VERSION 5.7 ;
  NOWIREEXTENSIONATPIN ON ;
  DIVIDERCHAR "/" ;
  BUSBITCHARS "[]" ;
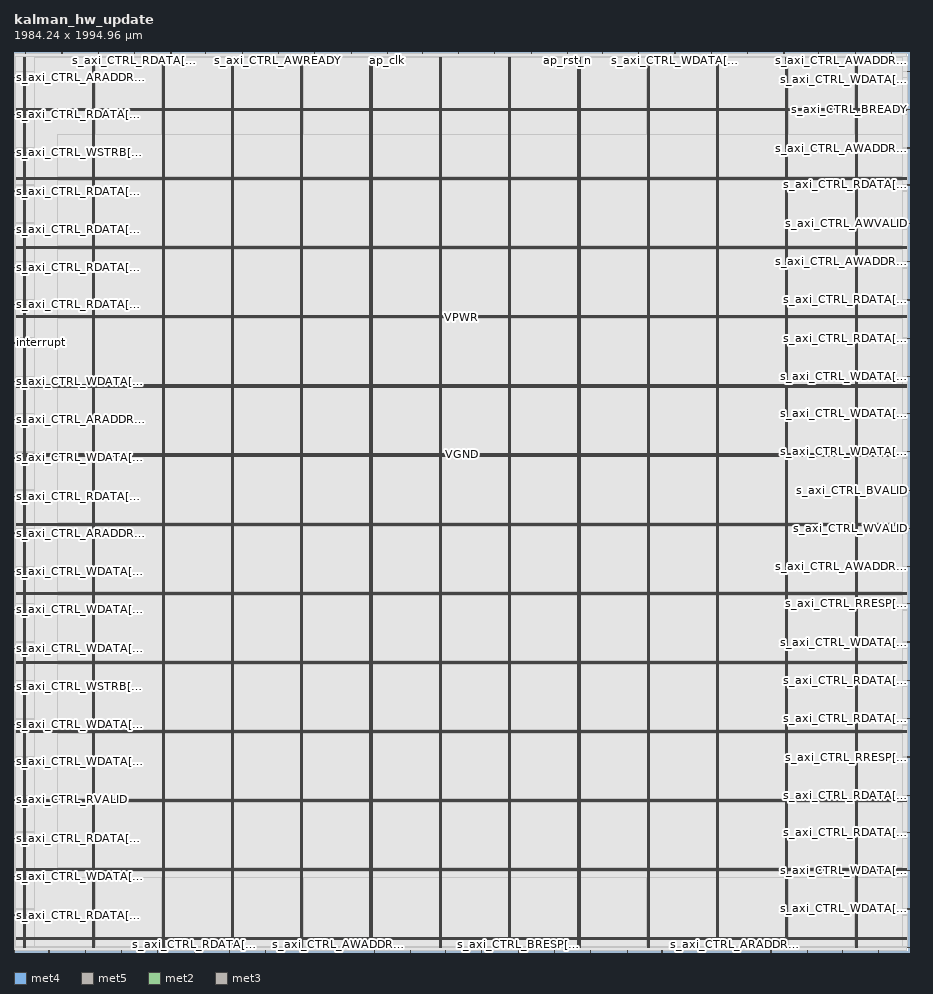
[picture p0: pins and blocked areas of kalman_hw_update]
MACRO kalman_hw_update
  CLASS BLOCK ;
  FOREIGN kalman_hw_update ;
  ORIGIN 0.000 0.000 ;
  SIZE 1984.245 BY 1994.965 ;
  PIN VGND
    DIRECTION INOUT ;
    USE GROUND ;
    PORT
      LAYER met4 ;
        RECT 24.340 10.640 25.940 1983.120 ;
    END
    PORT
      LAYER met4 ;
        RECT 177.940 10.640 179.540 1983.120 ;
    END
    PORT
      LAYER met4 ;
        RECT 331.540 10.640 333.140 1983.120 ;
    END
    PORT
      LAYER met4 ;
        RECT 485.140 10.640 486.740 1983.120 ;
    END
    PORT
      LAYER met4 ;
        RECT 638.740 10.640 640.340 1983.120 ;
    END
    PORT
      LAYER met4 ;
        RECT 792.340 10.640 793.940 1983.120 ;
    END
    PORT
      LAYER met4 ;
        RECT 945.940 10.640 947.540 1983.120 ;
    END
    PORT
      LAYER met4 ;
        RECT 1099.540 10.640 1101.140 1983.120 ;
    END
    PORT
      LAYER met4 ;
        RECT 1253.140 10.640 1254.740 1983.120 ;
    END
    PORT
      LAYER met4 ;
        RECT 1406.740 10.640 1408.340 1983.120 ;
    END
    PORT
      LAYER met4 ;
        RECT 1560.340 10.640 1561.940 1983.120 ;
    END
    PORT
      LAYER met4 ;
        RECT 1713.940 10.640 1715.540 1983.120 ;
    END
    PORT
      LAYER met4 ;
        RECT 1867.540 10.640 1869.140 1983.120 ;
    END
    PORT
      LAYER met5 ;
        RECT 5.280 30.030 1978.700 31.630 ;
    END
    PORT
      LAYER met5 ;
        RECT 5.280 183.210 1978.700 184.810 ;
    END
    PORT
      LAYER met5 ;
        RECT 5.280 336.390 1978.700 337.990 ;
    END
    PORT
      LAYER met5 ;
        RECT 5.280 489.570 1978.700 491.170 ;
    END
    PORT
      LAYER met5 ;
        RECT 5.280 642.750 1978.700 644.350 ;
    END
    PORT
      LAYER met5 ;
        RECT 5.280 795.930 1978.700 797.530 ;
    END
    PORT
      LAYER met5 ;
        RECT 5.280 949.110 1978.700 950.710 ;
    END
    PORT
      LAYER met5 ;
        RECT 5.280 1102.290 1978.700 1103.890 ;
    END
    PORT
      LAYER met5 ;
        RECT 5.280 1255.470 1978.700 1257.070 ;
    END
    PORT
      LAYER met5 ;
        RECT 5.280 1408.650 1978.700 1410.250 ;
    END
    PORT
      LAYER met5 ;
        RECT 5.280 1561.830 1978.700 1563.430 ;
    END
    PORT
      LAYER met5 ;
        RECT 5.280 1715.010 1978.700 1716.610 ;
    END
    PORT
      LAYER met5 ;
        RECT 5.280 1868.190 1978.700 1869.790 ;
    END
  END VGND
  PIN VPWR
    DIRECTION INOUT ;
    USE POWER ;
    PORT
      LAYER met4 ;
        RECT 21.040 10.640 22.640 1983.120 ;
    END
    PORT
      LAYER met4 ;
        RECT 174.640 10.640 176.240 1983.120 ;
    END
    PORT
      LAYER met4 ;
        RECT 328.240 10.640 329.840 1983.120 ;
    END
    PORT
      LAYER met4 ;
        RECT 481.840 10.640 483.440 1983.120 ;
    END
    PORT
      LAYER met4 ;
        RECT 635.440 10.640 637.040 1983.120 ;
    END
    PORT
      LAYER met4 ;
        RECT 789.040 10.640 790.640 1983.120 ;
    END
    PORT
      LAYER met4 ;
        RECT 942.640 10.640 944.240 1983.120 ;
    END
    PORT
      LAYER met4 ;
        RECT 1096.240 10.640 1097.840 1983.120 ;
    END
    PORT
      LAYER met4 ;
        RECT 1249.840 10.640 1251.440 1983.120 ;
    END
    PORT
      LAYER met4 ;
        RECT 1403.440 10.640 1405.040 1983.120 ;
    END
    PORT
      LAYER met4 ;
        RECT 1557.040 10.640 1558.640 1983.120 ;
    END
    PORT
      LAYER met4 ;
        RECT 1710.640 10.640 1712.240 1983.120 ;
    END
    PORT
      LAYER met4 ;
        RECT 1864.240 10.640 1865.840 1983.120 ;
    END
    PORT
      LAYER met5 ;
        RECT 5.280 26.730 1978.700 28.330 ;
    END
    PORT
      LAYER met5 ;
        RECT 5.280 179.910 1978.700 181.510 ;
    END
    PORT
      LAYER met5 ;
        RECT 5.280 333.090 1978.700 334.690 ;
    END
    PORT
      LAYER met5 ;
        RECT 5.280 486.270 1978.700 487.870 ;
    END
    PORT
      LAYER met5 ;
        RECT 5.280 639.450 1978.700 641.050 ;
    END
    PORT
      LAYER met5 ;
        RECT 5.280 792.630 1978.700 794.230 ;
    END
    PORT
      LAYER met5 ;
        RECT 5.280 945.810 1978.700 947.410 ;
    END
    PORT
      LAYER met5 ;
        RECT 5.280 1098.990 1978.700 1100.590 ;
    END
    PORT
      LAYER met5 ;
        RECT 5.280 1252.170 1978.700 1253.770 ;
    END
    PORT
      LAYER met5 ;
        RECT 5.280 1405.350 1978.700 1406.950 ;
    END
    PORT
      LAYER met5 ;
        RECT 5.280 1558.530 1978.700 1560.130 ;
    END
    PORT
      LAYER met5 ;
        RECT 5.280 1711.710 1978.700 1713.310 ;
    END
    PORT
      LAYER met5 ;
        RECT 5.280 1864.890 1978.700 1866.490 ;
    END
  END VPWR
  PIN ap_clk
    DIRECTION INPUT ;
    USE SIGNAL ;
    ANTENNAGATEAREA 0.990000 ;
    PORT
      LAYER met2 ;
        RECT 827.630 1990.965 827.910 1994.965 ;
    END
  END ap_clk
  PIN ap_rst_n
    DIRECTION INPUT ;
    USE SIGNAL ;
    ANTENNAGATEAREA 0.990000 ;
    PORT
      LAYER met2 ;
        RECT 1226.910 1990.965 1227.190 1994.965 ;
    END
  END ap_rst_n
  PIN interrupt
    DIRECTION OUTPUT TRISTATE ;
    USE SIGNAL ;
    ANTENNADIFFAREA 0.795200 ;
    PORT
      LAYER met3 ;
        RECT 0.000 1349.840 4.000 1350.440 ;
    END
  END interrupt
  PIN s_axi_CTRL_ARADDR[0]
    DIRECTION INPUT ;
    USE SIGNAL ;
    ANTENNAGATEAREA 0.990000 ;
    PORT
      LAYER met3 ;
        RECT 0.000 1938.040 4.000 1938.640 ;
    END
  END s_axi_CTRL_ARADDR[0]
  PIN s_axi_CTRL_ARADDR[1]
    DIRECTION INPUT ;
    USE SIGNAL ;
    ANTENNAGATEAREA 0.990000 ;
    PORT
      LAYER met2 ;
        RECT 1597.210 0.000 1597.490 4.000 ;
    END
  END s_axi_CTRL_ARADDR[1]
  PIN s_axi_CTRL_ARADDR[2]
    DIRECTION INPUT ;
    USE SIGNAL ;
    ANTENNAGATEAREA 0.426000 ;
    PORT
      LAYER met2 ;
        RECT 476.650 0.000 476.930 4.000 ;
    END
  END s_axi_CTRL_ARADDR[2]
  PIN s_axi_CTRL_ARADDR[3]
    DIRECTION INPUT ;
    USE SIGNAL ;
    ANTENNAGATEAREA 0.990000 ;
    PORT
      LAYER met2 ;
        RECT 747.130 1990.965 747.410 1994.965 ;
    END
  END s_axi_CTRL_ARADDR[3]
  PIN s_axi_CTRL_ARADDR[4]
    DIRECTION INPUT ;
    USE SIGNAL ;
    ANTENNAGATEAREA 0.742500 ;
    PORT
      LAYER met3 ;
        RECT 0.000 1179.840 4.000 1180.440 ;
    END
  END s_axi_CTRL_ARADDR[4]
  PIN s_axi_CTRL_ARADDR[5]
    DIRECTION INPUT ;
    USE SIGNAL ;
    ANTENNAGATEAREA 0.426000 ;
    PORT
      LAYER met3 ;
        RECT 0.000 928.240 4.000 928.840 ;
    END
  END s_axi_CTRL_ARADDR[5]
  PIN s_axi_CTRL_ARREADY
    DIRECTION OUTPUT TRISTATE ;
    USE SIGNAL ;
    ANTENNADIFFAREA 0.795200 ;
    PORT
      LAYER met2 ;
        RECT 238.370 0.000 238.650 4.000 ;
    END
  END s_axi_CTRL_ARREADY
  PIN s_axi_CTRL_ARVALID
    DIRECTION INPUT ;
    USE SIGNAL ;
    ANTENNAGATEAREA 0.990000 ;
    PORT
      LAYER met3 ;
        RECT 1980.245 10.240 1984.245 10.840 ;
    END
  END s_axi_CTRL_ARVALID
  PIN s_axi_CTRL_AWADDR[0]
    DIRECTION INPUT ;
    USE SIGNAL ;
    ANTENNAGATEAREA 0.426000 ;
    PORT
      LAYER met3 ;
        RECT 1980.245 1530.040 1984.245 1530.640 ;
    END
  END s_axi_CTRL_AWADDR[0]
  PIN s_axi_CTRL_AWADDR[1]
    DIRECTION INPUT ;
    USE SIGNAL ;
    ANTENNAGATEAREA 0.426000 ;
    PORT
      LAYER met2 ;
        RECT 1835.490 0.000 1835.770 4.000 ;
    END
  END s_axi_CTRL_AWADDR[1]
  PIN s_axi_CTRL_AWADDR[2]
    DIRECTION INPUT ;
    USE SIGNAL ;
    ANTENNAGATEAREA 0.990000 ;
    PORT
      LAYER met2 ;
        RECT 1944.970 1990.965 1945.250 1994.965 ;
    END
  END s_axi_CTRL_AWADDR[2]
  PIN s_axi_CTRL_AWADDR[3]
    DIRECTION INPUT ;
    USE SIGNAL ;
    ANTENNAGATEAREA 0.990000 ;
    PORT
      LAYER met3 ;
        RECT 1980.245 853.440 1984.245 854.040 ;
    END
  END s_axi_CTRL_AWADDR[3]
  PIN s_axi_CTRL_AWADDR[4]
    DIRECTION INPUT ;
    USE SIGNAL ;
    ANTENNAGATEAREA 0.426000 ;
    PORT
      LAYER met2 ;
        RECT 718.150 0.000 718.430 4.000 ;
    END
  END s_axi_CTRL_AWADDR[4]
  PIN s_axi_CTRL_AWADDR[5]
    DIRECTION INPUT ;
    USE SIGNAL ;
    ANTENNAGATEAREA 0.495000 ;
    PORT
      LAYER met3 ;
        RECT 1980.245 1781.640 1984.245 1782.240 ;
    END
  END s_axi_CTRL_AWADDR[5]
  PIN s_axi_CTRL_AWREADY
    DIRECTION OUTPUT TRISTATE ;
    USE SIGNAL ;
    ANTENNADIFFAREA 0.795200 ;
    PORT
      LAYER met2 ;
        RECT 586.130 1990.965 586.410 1994.965 ;
    END
  END s_axi_CTRL_AWREADY
  PIN s_axi_CTRL_AWVALID
    DIRECTION INPUT ;
    USE SIGNAL ;
    ANTENNAGATEAREA 0.990000 ;
    PORT
      LAYER met3 ;
        RECT 1980.245 1615.040 1984.245 1615.640 ;
    END
  END s_axi_CTRL_AWVALID
  PIN s_axi_CTRL_BREADY
    DIRECTION INPUT ;
    USE SIGNAL ;
    ANTENNAGATEAREA 0.213000 ;
    PORT
      LAYER met3 ;
        RECT 1980.245 1866.640 1984.245 1867.240 ;
    END
  END s_axi_CTRL_BREADY
  PIN s_axi_CTRL_BRESP[0]
    DIRECTION OUTPUT TRISTATE ;
    USE SIGNAL ;
    PORT
      LAYER met2 ;
        RECT 1117.430 0.000 1117.710 4.000 ;
    END
  END s_axi_CTRL_BRESP[0]
  PIN s_axi_CTRL_BRESP[1]
    DIRECTION OUTPUT TRISTATE ;
    USE SIGNAL ;
    PORT
      LAYER met2 ;
        RECT 1384.690 1990.965 1384.970 1994.965 ;
    END
  END s_axi_CTRL_BRESP[1]
  PIN s_axi_CTRL_BVALID
    DIRECTION OUTPUT TRISTATE ;
    USE SIGNAL ;
    ANTENNADIFFAREA 0.445500 ;
    PORT
      LAYER met3 ;
        RECT 1980.245 1023.440 1984.245 1024.040 ;
    END
  END s_axi_CTRL_BVALID
  PIN s_axi_CTRL_RDATA[0]
    DIRECTION OUTPUT TRISTATE ;
    USE SIGNAL ;
    ANTENNADIFFAREA 0.795200 ;
    PORT
      LAYER met3 ;
        RECT 1980.245 516.840 1984.245 517.440 ;
    END
  END s_axi_CTRL_RDATA[0]
  PIN s_axi_CTRL_RDATA[10]
    DIRECTION OUTPUT TRISTATE ;
    USE SIGNAL ;
    ANTENNADIFFAREA 0.795200 ;
    PORT
      LAYER met3 ;
        RECT 0.000 251.640 4.000 252.240 ;
    END
  END s_axi_CTRL_RDATA[10]
  PIN s_axi_CTRL_RDATA[11]
    DIRECTION OUTPUT TRISTATE ;
    USE SIGNAL ;
    ANTENNADIFFAREA 0.795200 ;
    PORT
      LAYER met2 ;
        RECT 798.650 0.000 798.930 4.000 ;
    END
  END s_axi_CTRL_RDATA[11]
  PIN s_axi_CTRL_RDATA[12]
    DIRECTION OUTPUT TRISTATE ;
    USE SIGNAL ;
    ANTENNADIFFAREA 0.795200 ;
    PORT
      LAYER met2 ;
        RECT 1677.710 0.000 1677.990 4.000 ;
    END
  END s_axi_CTRL_RDATA[12]
  PIN s_axi_CTRL_RDATA[13]
    DIRECTION OUTPUT TRISTATE ;
    USE SIGNAL ;
    ANTENNADIFFAREA 0.795200 ;
    PORT
      LAYER met2 ;
        RECT 904.910 1990.965 905.190 1994.965 ;
    END
  END s_axi_CTRL_RDATA[13]
  PIN s_axi_CTRL_RDATA[14]
    DIRECTION OUTPUT TRISTATE ;
    USE SIGNAL ;
    ANTENNADIFFAREA 0.795200 ;
    PORT
      LAYER met2 ;
        RECT 1304.190 1990.965 1304.470 1994.965 ;
    END
  END s_axi_CTRL_RDATA[14]
  PIN s_axi_CTRL_RDATA[15]
    DIRECTION OUTPUT TRISTATE ;
    USE SIGNAL ;
    ANTENNADIFFAREA 0.445500 ;
    PORT
      LAYER met3 ;
        RECT 1980.245 1700.040 1984.245 1700.640 ;
    END
  END s_axi_CTRL_RDATA[15]
  PIN s_axi_CTRL_RDATA[16]
    DIRECTION OUTPUT TRISTATE ;
    USE SIGNAL ;
    ANTENNADIFFAREA 0.445500 ;
    PORT
      LAYER met3 ;
        RECT 1980.245 346.840 1984.245 347.440 ;
    END
  END s_axi_CTRL_RDATA[16]
  PIN s_axi_CTRL_RDATA[17]
    DIRECTION OUTPUT TRISTATE ;
    USE SIGNAL ;
    ANTENNADIFFAREA 0.795200 ;
    PORT
      LAYER met2 ;
        RECT 985.410 1990.965 985.690 1994.965 ;
    END
  END s_axi_CTRL_RDATA[17]
  PIN s_axi_CTRL_RDATA[18]
    DIRECTION OUTPUT TRISTATE ;
    USE SIGNAL ;
    ANTENNADIFFAREA 0.795200 ;
    PORT
      LAYER met2 ;
        RECT 25.850 1990.965 26.130 1994.965 ;
    END
  END s_axi_CTRL_RDATA[18]
  PIN s_axi_CTRL_RDATA[19]
    DIRECTION OUTPUT TRISTATE ;
    USE SIGNAL ;
    ANTENNADIFFAREA 0.795200 ;
    PORT
      LAYER met2 ;
        RECT 1706.690 1990.965 1706.970 1994.965 ;
    END
  END s_axi_CTRL_RDATA[19]
  PIN s_axi_CTRL_RDATA[1]
    DIRECTION OUTPUT TRISTATE ;
    USE SIGNAL ;
    ANTENNADIFFAREA 0.795200 ;
    PORT
      LAYER met2 ;
        RECT 399.370 0.000 399.650 4.000 ;
    END
  END s_axi_CTRL_RDATA[1]
  PIN s_axi_CTRL_RDATA[20]
    DIRECTION OUTPUT TRISTATE ;
    USE SIGNAL ;
    ANTENNADIFFAREA 0.795200 ;
    PORT
      LAYER met2 ;
        RECT 666.630 1990.965 666.910 1994.965 ;
    END
  END s_axi_CTRL_RDATA[20]
  PIN s_axi_CTRL_RDATA[21]
    DIRECTION OUTPUT TRISTATE ;
    USE SIGNAL ;
    ANTENNADIFFAREA 0.445500 ;
    PORT
      LAYER met3 ;
        RECT 1980.245 1445.040 1984.245 1445.640 ;
    END
  END s_axi_CTRL_RDATA[21]
  PIN s_axi_CTRL_RDATA[22]
    DIRECTION OUTPUT TRISTATE ;
    USE SIGNAL ;
    ANTENNADIFFAREA 0.445500 ;
    PORT
      LAYER met3 ;
        RECT 1980.245 601.840 1984.245 602.440 ;
    END
  END s_axi_CTRL_RDATA[22]
  PIN s_axi_CTRL_RDATA[23]
    DIRECTION OUTPUT TRISTATE ;
    USE SIGNAL ;
    ANTENNADIFFAREA 0.795200 ;
    PORT
      LAYER met2 ;
        RECT 1146.410 1990.965 1146.690 1994.965 ;
    END
  END s_axi_CTRL_RDATA[23]
  PIN s_axi_CTRL_RDATA[24]
    DIRECTION OUTPUT TRISTATE ;
    USE SIGNAL ;
    ANTENNADIFFAREA 0.795200 ;
    PORT
      LAYER met2 ;
        RECT 1783.970 1990.965 1784.250 1994.965 ;
    END
  END s_axi_CTRL_RDATA[24]
  PIN s_axi_CTRL_RDATA[25]
    DIRECTION OUTPUT TRISTATE ;
    USE SIGNAL ;
    ANTENNADIFFAREA 0.795200 ;
    PORT
      LAYER met2 ;
        RECT 1915.990 0.000 1916.270 4.000 ;
    END
  END s_axi_CTRL_RDATA[25]
  PIN s_axi_CTRL_RDATA[26]
    DIRECTION OUTPUT TRISTATE ;
    USE SIGNAL ;
    ANTENNADIFFAREA 0.445500 ;
    PORT
      LAYER met3 ;
        RECT 1980.245 1360.040 1984.245 1360.640 ;
    END
  END s_axi_CTRL_RDATA[26]
  PIN s_axi_CTRL_RDATA[27]
    DIRECTION OUTPUT TRISTATE ;
    USE SIGNAL ;
    ANTENNADIFFAREA 0.795200 ;
    PORT
      LAYER met3 ;
        RECT 0.000 1434.840 4.000 1435.440 ;
    END
  END s_axi_CTRL_RDATA[27]
  PIN s_axi_CTRL_RDATA[28]
    DIRECTION OUTPUT TRISTATE ;
    USE SIGNAL ;
    ANTENNADIFFAREA 0.795200 ;
    PORT
      LAYER met2 ;
        RECT 1278.430 0.000 1278.710 4.000 ;
    END
  END s_axi_CTRL_RDATA[28]
  PIN s_axi_CTRL_RDATA[29]
    DIRECTION OUTPUT TRISTATE ;
    USE SIGNAL ;
    ANTENNADIFFAREA 0.795200 ;
    PORT
      LAYER met3 ;
        RECT 0.000 1009.840 4.000 1010.440 ;
    END
  END s_axi_CTRL_RDATA[29]
  PIN s_axi_CTRL_RDATA[2]
    DIRECTION OUTPUT TRISTATE ;
    USE SIGNAL ;
    ANTENNADIFFAREA 0.445500 ;
    PORT
      LAYER met3 ;
        RECT 1980.245 265.240 1984.245 265.840 ;
    END
  END s_axi_CTRL_RDATA[2]
  PIN s_axi_CTRL_RDATA[30]
    DIRECTION OUTPUT TRISTATE ;
    USE SIGNAL ;
    ANTENNADIFFAREA 0.795200 ;
    PORT
      LAYER met3 ;
        RECT 0.000 81.640 4.000 82.240 ;
    END
  END s_axi_CTRL_RDATA[30]
  PIN s_axi_CTRL_RDATA[31]
    DIRECTION OUTPUT TRISTATE ;
    USE SIGNAL ;
    ANTENNADIFFAREA 0.795200 ;
    PORT
      LAYER met3 ;
        RECT 0.000 1856.440 4.000 1857.040 ;
    END
  END s_axi_CTRL_RDATA[31]
  PIN s_axi_CTRL_RDATA[3]
    DIRECTION OUTPUT TRISTATE ;
    USE SIGNAL ;
    ANTENNADIFFAREA 0.795200 ;
    PORT
      LAYER met3 ;
        RECT 0.000 1601.440 4.000 1602.040 ;
    END
  END s_axi_CTRL_RDATA[3]
  PIN s_axi_CTRL_RDATA[4]
    DIRECTION OUTPUT TRISTATE ;
    USE SIGNAL ;
    ANTENNADIFFAREA 0.795200 ;
    PORT
      LAYER met3 ;
        RECT 0.000 1516.440 4.000 1517.040 ;
    END
  END s_axi_CTRL_RDATA[4]
  PIN s_axi_CTRL_RDATA[5]
    DIRECTION OUTPUT TRISTATE ;
    USE SIGNAL ;
    ANTENNADIFFAREA 0.795200 ;
    PORT
      LAYER met2 ;
        RECT 1436.210 0.000 1436.490 4.000 ;
    END
  END s_axi_CTRL_RDATA[5]
  PIN s_axi_CTRL_RDATA[6]
    DIRECTION OUTPUT TRISTATE ;
    USE SIGNAL ;
    ANTENNADIFFAREA 0.795200 ;
    PORT
      LAYER met3 ;
        RECT 0.000 1686.440 4.000 1687.040 ;
    END
  END s_axi_CTRL_RDATA[6]
  PIN s_axi_CTRL_RDATA[7]
    DIRECTION OUTPUT TRISTATE ;
    USE SIGNAL ;
    ANTENNADIFFAREA 0.795200 ;
    PORT
      LAYER met2 ;
        RECT 267.350 1990.965 267.630 1994.965 ;
    END
  END s_axi_CTRL_RDATA[7]
  PIN s_axi_CTRL_RDATA[8]
    DIRECTION OUTPUT TRISTATE ;
    USE SIGNAL ;
    ANTENNADIFFAREA 0.795200 ;
    PORT
      LAYER met2 ;
        RECT 157.870 0.000 158.150 4.000 ;
    END
  END s_axi_CTRL_RDATA[8]
  PIN s_axi_CTRL_RDATA[9]
    DIRECTION OUTPUT TRISTATE ;
    USE SIGNAL ;
    ANTENNADIFFAREA 0.795200 ;
    PORT
      LAYER met2 ;
        RECT 557.150 0.000 557.430 4.000 ;
    END
  END s_axi_CTRL_RDATA[9]
  PIN s_axi_CTRL_RREADY
    DIRECTION INPUT ;
    USE SIGNAL ;
    ANTENNAGATEAREA 0.990000 ;
    PORT
      LAYER met2 ;
        RECT 1758.210 0.000 1758.490 4.000 ;
    END
  END s_axi_CTRL_RREADY
  PIN s_axi_CTRL_RRESP[0]
    DIRECTION OUTPUT TRISTATE ;
    USE SIGNAL ;
    PORT
      LAYER met3 ;
        RECT 1980.245 771.840 1984.245 772.440 ;
    END
  END s_axi_CTRL_RRESP[0]
  PIN s_axi_CTRL_RRESP[1]
    DIRECTION OUTPUT TRISTATE ;
    USE SIGNAL ;
    PORT
      LAYER met3 ;
        RECT 1980.245 431.840 1984.245 432.440 ;
    END
  END s_axi_CTRL_RRESP[1]
  PIN s_axi_CTRL_RVALID
    DIRECTION OUTPUT TRISTATE ;
    USE SIGNAL ;
    ANTENNADIFFAREA 0.795200 ;
    PORT
      LAYER met3 ;
        RECT 0.000 336.640 4.000 337.240 ;
    END
  END s_axi_CTRL_RVALID
  PIN s_axi_CTRL_WDATA[0]
    DIRECTION INPUT ;
    USE SIGNAL ;
    ANTENNAGATEAREA 0.742500 ;
    PORT
      LAYER met3 ;
        RECT 0.000 166.640 4.000 167.240 ;
    END
  END s_axi_CTRL_WDATA[0]
  PIN s_axi_CTRL_WDATA[10]
    DIRECTION INPUT ;
    USE SIGNAL ;
    ANTENNAGATEAREA 0.990000 ;
    PORT
      LAYER met3 ;
        RECT 1980.245 95.240 1984.245 95.840 ;
    END
  END s_axi_CTRL_WDATA[10]
  PIN s_axi_CTRL_WDATA[11]
    DIRECTION INPUT ;
    USE SIGNAL ;
    ANTENNAGATEAREA 0.990000 ;
    PORT
      LAYER met2 ;
        RECT 347.850 1990.965 348.130 1994.965 ;
    END
  END s_axi_CTRL_WDATA[11]
  PIN s_axi_CTRL_WDATA[12]
    DIRECTION INPUT ;
    USE SIGNAL ;
    ANTENNAGATEAREA 0.852000 ;
    PORT
      LAYER met3 ;
        RECT 1980.245 686.840 1984.245 687.440 ;
    END
  END s_axi_CTRL_WDATA[12]
  PIN s_axi_CTRL_WDATA[13]
    DIRECTION INPUT ;
    USE SIGNAL ;
    ANTENNAGATEAREA 0.247500 ;
    PORT
      LAYER met3 ;
        RECT 0.000 843.240 4.000 843.840 ;
    END
  END s_axi_CTRL_WDATA[13]
  PIN s_axi_CTRL_WDATA[14]
    DIRECTION INPUT ;
    USE SIGNAL ;
    ANTENNAGATEAREA 0.852000 ;
    PORT
      LAYER met2 ;
        RECT 1516.710 0.000 1516.990 4.000 ;
    END
  END s_axi_CTRL_WDATA[14]
  PIN s_axi_CTRL_WDATA[15]
    DIRECTION INPUT ;
    USE SIGNAL ;
    ANTENNAGATEAREA 0.990000 ;
    PORT
      LAYER met3 ;
        RECT 1980.245 1275.040 1984.245 1275.640 ;
    END
  END s_axi_CTRL_WDATA[15]
  PIN s_axi_CTRL_WDATA[16]
    DIRECTION INPUT ;
    USE SIGNAL ;
    ANTENNAGATEAREA 0.426000 ;
    PORT
      LAYER met3 ;
        RECT 0.000 421.640 4.000 422.240 ;
    END
  END s_axi_CTRL_WDATA[16]
  PIN s_axi_CTRL_WDATA[17]
    DIRECTION INPUT ;
    USE SIGNAL ;
    ANTENNAGATEAREA 0.742500 ;
    PORT
      LAYER met3 ;
        RECT 0.000 1264.840 4.000 1265.440 ;
    END
  END s_axi_CTRL_WDATA[17]
  PIN s_axi_CTRL_WDATA[18]
    DIRECTION INPUT ;
    USE SIGNAL ;
    ANTENNAGATEAREA 0.495000 ;
    PORT
      LAYER met2 ;
        RECT 956.430 0.000 956.710 4.000 ;
    END
  END s_axi_CTRL_WDATA[18]
  PIN s_axi_CTRL_WDATA[19]
    DIRECTION INPUT ;
    USE SIGNAL ;
    ANTENNAGATEAREA 0.742500 ;
    PORT
      LAYER met2 ;
        RECT 0.090 0.000 0.370 4.000 ;
    END
  END s_axi_CTRL_WDATA[19]
  PIN s_axi_CTRL_WDATA[1]
    DIRECTION INPUT ;
    USE SIGNAL ;
    ANTENNAGATEAREA 0.852000 ;
    PORT
      LAYER met2 ;
        RECT 1197.930 0.000 1198.210 4.000 ;
    END
  END s_axi_CTRL_WDATA[1]
  PIN s_axi_CTRL_WDATA[20]
    DIRECTION INPUT ;
    USE SIGNAL ;
    ANTENNAGATEAREA 0.742500 ;
    PORT
      LAYER met2 ;
        RECT 505.630 1990.965 505.910 1994.965 ;
    END
  END s_axi_CTRL_WDATA[20]
  PIN s_axi_CTRL_WDATA[21]
    DIRECTION INPUT ;
    USE SIGNAL ;
    ANTENNAGATEAREA 0.990000 ;
    PORT
      LAYER met2 ;
        RECT 1065.910 1990.965 1066.190 1994.965 ;
    END
  END s_axi_CTRL_WDATA[21]
  PIN s_axi_CTRL_WDATA[22]
    DIRECTION INPUT ;
    USE SIGNAL ;
    ANTENNAGATEAREA 0.247500 ;
    PORT
      LAYER met3 ;
        RECT 0.000 673.240 4.000 673.840 ;
    END
  END s_axi_CTRL_WDATA[22]
  PIN s_axi_CTRL_WDATA[23]
    DIRECTION INPUT ;
    USE SIGNAL ;
    ANTENNAGATEAREA 0.990000 ;
    PORT
      LAYER met2 ;
        RECT 106.350 1990.965 106.630 1994.965 ;
    END
  END s_axi_CTRL_WDATA[23]
  PIN s_axi_CTRL_WDATA[24]
    DIRECTION INPUT ;
    USE SIGNAL ;
    ANTENNAGATEAREA 0.426000 ;
    PORT
      LAYER met3 ;
        RECT 0.000 1094.840 4.000 1095.440 ;
    END
  END s_axi_CTRL_WDATA[24]
  PIN s_axi_CTRL_WDATA[25]
    DIRECTION INPUT ;
    USE SIGNAL ;
    ANTENNAGATEAREA 0.742500 ;
    PORT
      LAYER met2 ;
        RECT 77.370 0.000 77.650 4.000 ;
    END
  END s_axi_CTRL_WDATA[25]
  PIN s_axi_CTRL_WDATA[26]
    DIRECTION INPUT ;
    USE SIGNAL ;
    ANTENNAGATEAREA 0.990000 ;
    PORT
      LAYER met2 ;
        RECT 1864.470 1990.965 1864.750 1994.965 ;
    END
  END s_axi_CTRL_WDATA[26]
  PIN s_axi_CTRL_WDATA[27]
    DIRECTION INPUT ;
    USE SIGNAL ;
    ANTENNAGATEAREA 0.990000 ;
    PORT
      LAYER met2 ;
        RECT 1465.190 1990.965 1465.470 1994.965 ;
    END
  END s_axi_CTRL_WDATA[27]
  PIN s_axi_CTRL_WDATA[28]
    DIRECTION INPUT ;
    USE SIGNAL ;
    ANTENNAGATEAREA 0.495000 ;
    PORT
      LAYER met2 ;
        RECT 879.150 0.000 879.430 4.000 ;
    END
  END s_axi_CTRL_WDATA[28]
  PIN s_axi_CTRL_WDATA[29]
    DIRECTION INPUT ;
    USE SIGNAL ;
    ANTENNAGATEAREA 0.990000 ;
    PORT
      LAYER met3 ;
        RECT 1980.245 1951.640 1984.245 1952.240 ;
    END
  END s_axi_CTRL_WDATA[29]
  PIN s_axi_CTRL_WDATA[2]
    DIRECTION INPUT ;
    USE SIGNAL ;
    ANTENNAGATEAREA 0.990000 ;
    PORT
      LAYER met3 ;
        RECT 1980.245 180.240 1984.245 180.840 ;
    END
  END s_axi_CTRL_WDATA[2]
  PIN s_axi_CTRL_WDATA[30]
    DIRECTION INPUT ;
    USE SIGNAL ;
    ANTENNAGATEAREA 0.247500 ;
    PORT
      LAYER met3 ;
        RECT 0.000 503.240 4.000 503.840 ;
    END
  END s_axi_CTRL_WDATA[30]
  PIN s_axi_CTRL_WDATA[31]
    DIRECTION INPUT ;
    USE SIGNAL ;
    ANTENNAGATEAREA 0.990000 ;
    PORT
      LAYER met3 ;
        RECT 1980.245 1108.440 1984.245 1109.040 ;
    END
  END s_axi_CTRL_WDATA[31]
  PIN s_axi_CTRL_WDATA[3]
    DIRECTION INPUT ;
    USE SIGNAL ;
    ANTENNAGATEAREA 0.426000 ;
    PORT
      LAYER met2 ;
        RECT 318.870 0.000 319.150 4.000 ;
    END
  END s_axi_CTRL_WDATA[3]
  PIN s_axi_CTRL_WDATA[4]
    DIRECTION INPUT ;
    USE SIGNAL ;
    ANTENNAGATEAREA 0.247500 ;
    PORT
      LAYER met2 ;
        RECT 637.650 0.000 637.930 4.000 ;
    END
  END s_axi_CTRL_WDATA[4]
  PIN s_axi_CTRL_WDATA[5]
    DIRECTION INPUT ;
    USE SIGNAL ;
    ANTENNAGATEAREA 0.247500 ;
    PORT
      LAYER met3 ;
        RECT 0.000 758.240 4.000 758.840 ;
    END
  END s_axi_CTRL_WDATA[5]
  PIN s_axi_CTRL_WDATA[6]
    DIRECTION INPUT ;
    USE SIGNAL ;
    ANTENNAGATEAREA 0.990000 ;
    PORT
      LAYER met3 ;
        RECT 1980.245 1193.440 1984.245 1194.040 ;
    END
  END s_axi_CTRL_WDATA[6]
  PIN s_axi_CTRL_WDATA[7]
    DIRECTION INPUT ;
    USE SIGNAL ;
    ANTENNAGATEAREA 0.742500 ;
    PORT
      LAYER met2 ;
        RECT 1036.930 0.000 1037.210 4.000 ;
    END
  END s_axi_CTRL_WDATA[7]
  PIN s_axi_CTRL_WDATA[8]
    DIRECTION INPUT ;
    USE SIGNAL ;
    ANTENNAGATEAREA 0.990000 ;
    PORT
      LAYER met2 ;
        RECT 1626.190 1990.965 1626.470 1994.965 ;
    END
  END s_axi_CTRL_WDATA[8]
  PIN s_axi_CTRL_WDATA[9]
    DIRECTION INPUT ;
    USE SIGNAL ;
    ANTENNAGATEAREA 0.990000 ;
    PORT
      LAYER met2 ;
        RECT 1545.690 1990.965 1545.970 1994.965 ;
    END
  END s_axi_CTRL_WDATA[9]
  PIN s_axi_CTRL_WREADY
    DIRECTION OUTPUT TRISTATE ;
    USE SIGNAL ;
    ANTENNADIFFAREA 0.795200 ;
    PORT
      LAYER met2 ;
        RECT 186.850 1990.965 187.130 1994.965 ;
    END
  END s_axi_CTRL_WREADY
  PIN s_axi_CTRL_WSTRB[0]
    DIRECTION INPUT ;
    USE SIGNAL ;
    ANTENNAGATEAREA 0.852000 ;
    PORT
      LAYER met2 ;
        RECT 425.130 1990.965 425.410 1994.965 ;
    END
  END s_axi_CTRL_WSTRB[0]
  PIN s_axi_CTRL_WSTRB[1]
    DIRECTION INPUT ;
    USE SIGNAL ;
    ANTENNAGATEAREA 0.852000 ;
    PORT
      LAYER met2 ;
        RECT 1358.930 0.000 1359.210 4.000 ;
    END
  END s_axi_CTRL_WSTRB[1]
  PIN s_axi_CTRL_WSTRB[2]
    DIRECTION INPUT ;
    USE SIGNAL ;
    ANTENNAGATEAREA 0.247500 ;
    PORT
      LAYER met3 ;
        RECT 0.000 588.240 4.000 588.840 ;
    END
  END s_axi_CTRL_WSTRB[2]
  PIN s_axi_CTRL_WSTRB[3]
    DIRECTION INPUT ;
    USE SIGNAL ;
    ANTENNAGATEAREA 0.990000 ;
    PORT
      LAYER met3 ;
        RECT 0.000 1771.440 4.000 1772.040 ;
    END
  END s_axi_CTRL_WSTRB[3]
  PIN s_axi_CTRL_WVALID
    DIRECTION INPUT ;
    USE SIGNAL ;
    ANTENNAGATEAREA 0.990000 ;
    PORT
      LAYER met3 ;
        RECT 1980.245 938.440 1984.245 939.040 ;
    END
  END s_axi_CTRL_WVALID
  OBS
      LAYER li1 ;
        RECT 5.520 10.795 1978.460 1982.965 ;
      LAYER met1 ;
        RECT 0.070 9.560 1978.460 1984.200 ;
      LAYER met2 ;
        RECT 0.100 1990.685 25.570 1991.450 ;
        RECT 26.410 1990.685 106.070 1991.450 ;
        RECT 106.910 1990.685 186.570 1991.450 ;
        RECT 187.410 1990.685 267.070 1991.450 ;
        RECT 267.910 1990.685 347.570 1991.450 ;
        RECT 348.410 1990.685 424.850 1991.450 ;
        RECT 425.690 1990.685 505.350 1991.450 ;
        RECT 506.190 1990.685 585.850 1991.450 ;
        RECT 586.690 1990.685 666.350 1991.450 ;
        RECT 667.190 1990.685 746.850 1991.450 ;
        RECT 747.690 1990.685 827.350 1991.450 ;
        RECT 828.190 1990.685 904.630 1991.450 ;
        RECT 905.470 1990.685 985.130 1991.450 ;
        RECT 985.970 1990.685 1065.630 1991.450 ;
        RECT 1066.470 1990.685 1146.130 1991.450 ;
        RECT 1146.970 1990.685 1226.630 1991.450 ;
        RECT 1227.470 1990.685 1303.910 1991.450 ;
        RECT 1304.750 1990.685 1384.410 1991.450 ;
        RECT 1385.250 1990.685 1464.910 1991.450 ;
        RECT 1465.750 1990.685 1545.410 1991.450 ;
        RECT 1546.250 1990.685 1625.910 1991.450 ;
        RECT 1626.750 1990.685 1706.410 1991.450 ;
        RECT 1707.250 1990.685 1783.690 1991.450 ;
        RECT 1784.530 1990.685 1864.190 1991.450 ;
        RECT 1865.030 1990.685 1944.690 1991.450 ;
        RECT 1945.530 1990.685 1978.370 1991.450 ;
        RECT 0.100 4.280 1978.370 1990.685 ;
        RECT 0.650 3.670 77.090 4.280 ;
        RECT 77.930 3.670 157.590 4.280 ;
        RECT 158.430 3.670 238.090 4.280 ;
        RECT 238.930 3.670 318.590 4.280 ;
        RECT 319.430 3.670 399.090 4.280 ;
        RECT 399.930 3.670 476.370 4.280 ;
        RECT 477.210 3.670 556.870 4.280 ;
        RECT 557.710 3.670 637.370 4.280 ;
        RECT 638.210 3.670 717.870 4.280 ;
        RECT 718.710 3.670 798.370 4.280 ;
        RECT 799.210 3.670 878.870 4.280 ;
        RECT 879.710 3.670 956.150 4.280 ;
        RECT 956.990 3.670 1036.650 4.280 ;
        RECT 1037.490 3.670 1117.150 4.280 ;
        RECT 1117.990 3.670 1197.650 4.280 ;
        RECT 1198.490 3.670 1278.150 4.280 ;
        RECT 1278.990 3.670 1358.650 4.280 ;
        RECT 1359.490 3.670 1435.930 4.280 ;
        RECT 1436.770 3.670 1516.430 4.280 ;
        RECT 1517.270 3.670 1596.930 4.280 ;
        RECT 1597.770 3.670 1677.430 4.280 ;
        RECT 1678.270 3.670 1757.930 4.280 ;
        RECT 1758.770 3.670 1835.210 4.280 ;
        RECT 1836.050 3.670 1915.710 4.280 ;
        RECT 1916.550 3.670 1978.370 4.280 ;
      LAYER met3 ;
        RECT 3.990 1952.640 1980.245 1984.745 ;
        RECT 3.990 1951.240 1979.845 1952.640 ;
        RECT 3.990 1939.040 1980.245 1951.240 ;
        RECT 4.400 1937.640 1980.245 1939.040 ;
        RECT 3.990 1867.640 1980.245 1937.640 ;
        RECT 3.990 1866.240 1979.845 1867.640 ;
        RECT 3.990 1857.440 1980.245 1866.240 ;
        RECT 4.400 1856.040 1980.245 1857.440 ;
        RECT 3.990 1782.640 1980.245 1856.040 ;
        RECT 3.990 1781.240 1979.845 1782.640 ;
        RECT 3.990 1772.440 1980.245 1781.240 ;
        RECT 4.400 1771.040 1980.245 1772.440 ;
        RECT 3.990 1701.040 1980.245 1771.040 ;
        RECT 3.990 1699.640 1979.845 1701.040 ;
        RECT 3.990 1687.440 1980.245 1699.640 ;
        RECT 4.400 1686.040 1980.245 1687.440 ;
        RECT 3.990 1616.040 1980.245 1686.040 ;
        RECT 3.990 1614.640 1979.845 1616.040 ;
        RECT 3.990 1602.440 1980.245 1614.640 ;
        RECT 4.400 1601.040 1980.245 1602.440 ;
        RECT 3.990 1531.040 1980.245 1601.040 ;
        RECT 3.990 1529.640 1979.845 1531.040 ;
        RECT 3.990 1517.440 1980.245 1529.640 ;
        RECT 4.400 1516.040 1980.245 1517.440 ;
        RECT 3.990 1446.040 1980.245 1516.040 ;
        RECT 3.990 1444.640 1979.845 1446.040 ;
        RECT 3.990 1435.840 1980.245 1444.640 ;
        RECT 4.400 1434.440 1980.245 1435.840 ;
        RECT 3.990 1361.040 1980.245 1434.440 ;
        RECT 3.990 1359.640 1979.845 1361.040 ;
        RECT 3.990 1350.840 1980.245 1359.640 ;
        RECT 4.400 1349.440 1980.245 1350.840 ;
        RECT 3.990 1276.040 1980.245 1349.440 ;
        RECT 3.990 1274.640 1979.845 1276.040 ;
        RECT 3.990 1265.840 1980.245 1274.640 ;
        RECT 4.400 1264.440 1980.245 1265.840 ;
        RECT 3.990 1194.440 1980.245 1264.440 ;
        RECT 3.990 1193.040 1979.845 1194.440 ;
        RECT 3.990 1180.840 1980.245 1193.040 ;
        RECT 4.400 1179.440 1980.245 1180.840 ;
        RECT 3.990 1109.440 1980.245 1179.440 ;
        RECT 3.990 1108.040 1979.845 1109.440 ;
        RECT 3.990 1095.840 1980.245 1108.040 ;
        RECT 4.400 1094.440 1980.245 1095.840 ;
        RECT 3.990 1024.440 1980.245 1094.440 ;
        RECT 3.990 1023.040 1979.845 1024.440 ;
        RECT 3.990 1010.840 1980.245 1023.040 ;
        RECT 4.400 1009.440 1980.245 1010.840 ;
        RECT 3.990 939.440 1980.245 1009.440 ;
        RECT 3.990 938.040 1979.845 939.440 ;
        RECT 3.990 929.240 1980.245 938.040 ;
        RECT 4.400 927.840 1980.245 929.240 ;
        RECT 3.990 854.440 1980.245 927.840 ;
        RECT 3.990 853.040 1979.845 854.440 ;
        RECT 3.990 844.240 1980.245 853.040 ;
        RECT 4.400 842.840 1980.245 844.240 ;
        RECT 3.990 772.840 1980.245 842.840 ;
        RECT 3.990 771.440 1979.845 772.840 ;
        RECT 3.990 759.240 1980.245 771.440 ;
        RECT 4.400 757.840 1980.245 759.240 ;
        RECT 3.990 687.840 1980.245 757.840 ;
        RECT 3.990 686.440 1979.845 687.840 ;
        RECT 3.990 674.240 1980.245 686.440 ;
        RECT 4.400 672.840 1980.245 674.240 ;
        RECT 3.990 602.840 1980.245 672.840 ;
        RECT 3.990 601.440 1979.845 602.840 ;
        RECT 3.990 589.240 1980.245 601.440 ;
        RECT 4.400 587.840 1980.245 589.240 ;
        RECT 3.990 517.840 1980.245 587.840 ;
        RECT 3.990 516.440 1979.845 517.840 ;
        RECT 3.990 504.240 1980.245 516.440 ;
        RECT 4.400 502.840 1980.245 504.240 ;
        RECT 3.990 432.840 1980.245 502.840 ;
        RECT 3.990 431.440 1979.845 432.840 ;
        RECT 3.990 422.640 1980.245 431.440 ;
        RECT 4.400 421.240 1980.245 422.640 ;
        RECT 3.990 347.840 1980.245 421.240 ;
        RECT 3.990 346.440 1979.845 347.840 ;
        RECT 3.990 337.640 1980.245 346.440 ;
        RECT 4.400 336.240 1980.245 337.640 ;
        RECT 3.990 266.240 1980.245 336.240 ;
        RECT 3.990 264.840 1979.845 266.240 ;
        RECT 3.990 252.640 1980.245 264.840 ;
        RECT 4.400 251.240 1980.245 252.640 ;
        RECT 3.990 181.240 1980.245 251.240 ;
        RECT 3.990 179.840 1979.845 181.240 ;
        RECT 3.990 167.640 1980.245 179.840 ;
        RECT 4.400 166.240 1980.245 167.640 ;
        RECT 3.990 96.240 1980.245 166.240 ;
        RECT 3.990 94.840 1979.845 96.240 ;
        RECT 3.990 82.640 1980.245 94.840 ;
        RECT 4.400 81.240 1980.245 82.640 ;
        RECT 3.990 11.240 1980.245 81.240 ;
        RECT 3.990 10.375 1979.845 11.240 ;
      LAYER met4 ;
        RECT 46.295 1983.520 1968.930 1984.745 ;
        RECT 46.295 11.735 174.240 1983.520 ;
        RECT 176.640 11.735 177.540 1983.520 ;
        RECT 179.940 11.735 327.840 1983.520 ;
        RECT 330.240 11.735 331.140 1983.520 ;
        RECT 333.540 11.735 481.440 1983.520 ;
        RECT 483.840 11.735 484.740 1983.520 ;
        RECT 487.140 11.735 635.040 1983.520 ;
        RECT 637.440 11.735 638.340 1983.520 ;
        RECT 640.740 11.735 788.640 1983.520 ;
        RECT 791.040 11.735 791.940 1983.520 ;
        RECT 794.340 11.735 942.240 1983.520 ;
        RECT 944.640 11.735 945.540 1983.520 ;
        RECT 947.940 11.735 1095.840 1983.520 ;
        RECT 1098.240 11.735 1099.140 1983.520 ;
        RECT 1101.540 11.735 1249.440 1983.520 ;
        RECT 1251.840 11.735 1252.740 1983.520 ;
        RECT 1255.140 11.735 1403.040 1983.520 ;
        RECT 1405.440 11.735 1406.340 1983.520 ;
        RECT 1408.740 11.735 1556.640 1983.520 ;
        RECT 1559.040 11.735 1559.940 1983.520 ;
        RECT 1562.340 11.735 1710.240 1983.520 ;
        RECT 1712.640 11.735 1713.540 1983.520 ;
        RECT 1715.940 11.735 1863.840 1983.520 ;
        RECT 1866.240 11.735 1867.140 1983.520 ;
        RECT 1869.540 11.735 1968.930 1983.520 ;
      LAYER met5 ;
        RECT 95.340 1718.210 1969.140 1811.300 ;
        RECT 95.340 1565.030 1969.140 1710.110 ;
        RECT 95.340 1411.850 1969.140 1556.930 ;
        RECT 95.340 1258.670 1969.140 1403.750 ;
        RECT 95.340 1105.490 1969.140 1250.570 ;
        RECT 95.340 952.310 1969.140 1097.390 ;
        RECT 95.340 799.130 1969.140 944.210 ;
        RECT 95.340 645.950 1969.140 791.030 ;
        RECT 95.340 492.770 1969.140 637.850 ;
        RECT 95.340 339.590 1969.140 484.670 ;
        RECT 95.340 186.410 1969.140 331.490 ;
        RECT 95.340 164.100 1969.140 178.310 ;
  END
END kalman_hw_update
END LIBRARY

